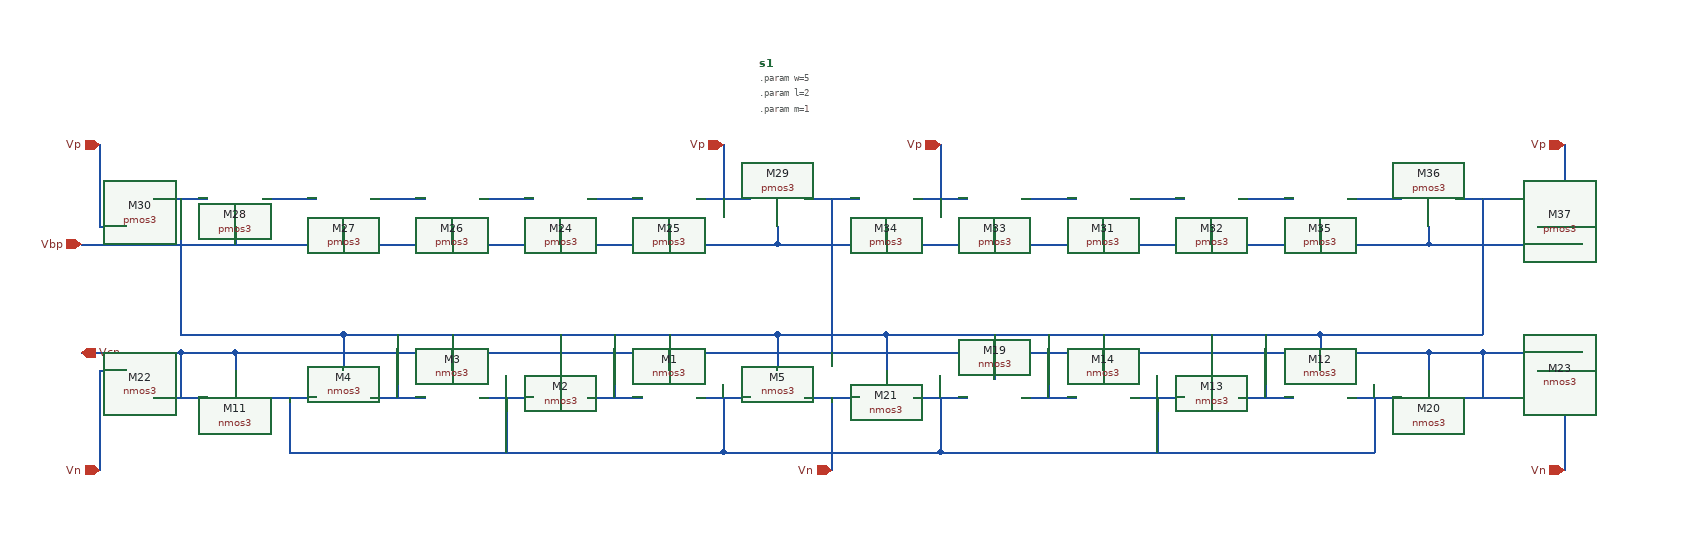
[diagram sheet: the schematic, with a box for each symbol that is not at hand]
v {xschem version=2.9.9 file_version=1.2 }
G {}
K {}
V {}
S {}
E {}
N -1100 -150 -1040 -150 { lab=#net1}
N -1220 -150 -1160 -150 { lab=#net2}
N -1340 -150 -1280 -150 { lab=#net1}
N -1460 -150 -1400 -150 { lab=#net2}
N -980 -150 -920 -150 { lab=#net2}
N -830 -150 -830 -70 { lab=Vn}
N -1370 -220 -890 -220 { lab=#net1}
N -1430 -150 -1430 -90 { lab=#net2}
N -1430 -90 -950 -90 { lab=#net2}
N -950 -150 -950 -90 { lab=#net2}
N -1190 -150 -1190 -90 { lab=#net2}
N -1580 -150 -1520 -150 { lab=Vcn}
N -1550 -200 -1550 -150 { lab=Vcn}
N -1550 -200 -1490 -200 { lab=Vcn}
N -1490 -200 -1490 -180 { lab=Vcn}
N -1370 -220 -1370 -180 { lab=#net1}
N -1250 -220 -1250 -180 { lab=#net1}
N -1130 -220 -1130 -180 { lab=#net1}
N -1010 -220 -1010 -180 { lab=#net1}
N -890 -220 -890 -180 { lab=#net1}
N -380 -150 -320 -150 { lab=#net1}
N -500 -150 -440 -150 { lab=#net2}
N -620 -150 -560 -150 { lab=#net1}
N -740 -150 -680 -150 { lab=#net2}
N -260 -150 -200 -150 { lab=#net2}
N -860 -150 -800 -150 { lab=Vn}
N -770 -220 -770 -180 { lab=#net1}
N -770 -220 -290 -220 { lab=#net1}
N -290 -220 -290 -180 { lab=#net1}
N -710 -150 -710 -90 { lab=#net2}
N -470 -150 -470 -90 { lab=#net2}
N -230 -150 -230 -90 { lab=#net2}
N -710 -90 -230 -90 { lab=#net2}
N -170 -200 -170 -180 { lab=Vcn}
N -140 -150 -80 -150 { lab=Vcn}
N -110 -200 -110 -150 { lab=Vcn}
N -170 -200 -110 -200 { lab=Vcn}
N -650 -220 -650 -170 { lab=#net1}
N -530 -220 -530 -180 { lab=#net1}
N -410 -220 -410 -180 { lab=#net1}
N -1490 -200 -170 -200 { lab=Vcn}
N -1640 -180 -1610 -180 { lab=Vn}
N -1640 -180 -1640 -70 { lab=Vn}
N -1660 -200 -1550 -200 { lab=Vcn}
N -50 -180 -20 -180 { lab=Vn}
N -20 -180 -20 -70 { lab=Vn}
N -110 -200 0 -200 { lab=Vcn}
N -1100 -370 -1040 -370 { lab=#net3}
N -1220 -370 -1160 -370 { lab=#net4}
N -1340 -370 -1280 -370 { lab=#net5}
N -1460 -370 -1400 -370 { lab=Vp}
N -1490 -340 -1490 -320 { lab=Vbp}
N -1370 -340 -1370 -320 { lab=Vbp}
N -1250 -340 -1250 -320 { lab=Vbp}
N -1130 -340 -1130 -320 { lab=Vbp}
N -1010 -340 -1010 -320 { lab=Vbp}
N -980 -370 -920 -370 { lab=#net6}
N -890 -340 -890 -320 { lab=Vbp}
N -950 -430 -950 -370 { lab=Vp}
N -1580 -370 -1520 -370 { lab=Vcn}
N -1640 -340 -1610 -340 { lab=Vp}
N -1640 -370 -1640 -340 { lab=Vp}
N -1640 -430 -1640 -370 { lab=Vp}
N -1660 -320 -890 -320 { lab=Vbp}
N -860 -370 -800 -370 { lab=#net1}
N -890 -220 -770 -220 { lab=#net1}
N -500 -370 -440 -370 { lab=#net7}
N -620 -370 -560 -370 { lab=#net8}
N -740 -370 -680 -370 { lab=#net9}
N -770 -340 -770 -320 { lab=Vbp}
N -650 -340 -650 -320 { lab=Vbp}
N -530 -340 -530 -320 { lab=Vbp}
N -410 -340 -410 -320 { lab=Vbp}
N -380 -370 -320 -370 { lab=#net10}
N -290 -340 -290 -320 { lab=Vbp}
N -260 -370 -200 -370 { lab=Vp}
N -170 -340 -170 -320 { lab=Vbp}
N -140 -370 -80 -370 { lab=Vcn}
N -890 -320 -170 -320 { lab=Vbp}
N -170 -320 0 -320 { lab=Vbp}
N -50 -340 -20 -340 { lab=Vp}
N -20 -430 -20 -340 { lab=Vp}
N -950 -90 -710 -90 { lab=#net2}
N -350 -220 -350 -150 { lab=#net1}
N -590 -220 -590 -150 { lab=#net1}
N -1070 -220 -1070 -150 { lab=#net1}
N -1310 -220 -1310 -150 { lab=#net1}
N -830 -370 -830 -200 {}
N -1550 -370 -1550 -220 {}
N -710 -430 -710 -370 { lab=Vp}
N -110 -370 -110 -220 {}
N -290 -220 -110 -220 {}
N -1550 -220 -1370 -220 {}
C {devices/code_shown.sym} -910 -520 0 0 {name=s1 only_toplevel=false value="
.param w=5
.param l=2
.param m=1
"}
C {madvlsi/nmos3.sym} -1010 -150 1 0 {name=M1
L=l
W=w
body=GND
nf=1
mult=m
ad="'int((nf+1)/2) * W/nf * 0.29'" 
pd="'2*int((nf+1)/2) * (W/nf + 0.29)'"
as="'int((nf+2)/2) * W/nf * 0.29'" 
ps="'2*int((nf+2)/2) * (W/nf + 0.29)'"
nrd="'0.29 / W'" nrs="'0.29 / W'"
sa=0 sb=0 sd=0
model=nfet_01v8
spiceprefix=X
}
C {madvlsi/nmos3.sym} -1130 -150 1 0 {name=M2
L=l
W=w
body=GND
nf=1
mult=m
ad="'int((nf+1)/2) * W/nf * 0.29'" 
pd="'2*int((nf+1)/2) * (W/nf + 0.29)'"
as="'int((nf+2)/2) * W/nf * 0.29'" 
ps="'2*int((nf+2)/2) * (W/nf + 0.29)'"
nrd="'0.29 / W'" nrs="'0.29 / W'"
sa=0 sb=0 sd=0
model=nfet_01v8
spiceprefix=X
}
C {madvlsi/nmos3.sym} -1250 -150 1 0 {name=M3
L=l
W=w
body=GND
nf=1
mult=m
ad="'int((nf+1)/2) * W/nf * 0.29'" 
pd="'2*int((nf+1)/2) * (W/nf + 0.29)'"
as="'int((nf+2)/2) * W/nf * 0.29'" 
ps="'2*int((nf+2)/2) * (W/nf + 0.29)'"
nrd="'0.29 / W'" nrs="'0.29 / W'"
sa=0 sb=0 sd=0
model=nfet_01v8
spiceprefix=X
}
C {madvlsi/nmos3.sym} -1370 -150 1 0 {name=M4
L=l
W=w
body=GND
nf=1
mult=m
ad="'int((nf+1)/2) * W/nf * 0.29'" 
pd="'2*int((nf+1)/2) * (W/nf + 0.29)'"
as="'int((nf+2)/2) * W/nf * 0.29'" 
ps="'2*int((nf+2)/2) * (W/nf + 0.29)'"
nrd="'0.29 / W'" nrs="'0.29 / W'"
sa=0 sb=0 sd=0
model=nfet_01v8
spiceprefix=X
}
C {madvlsi/nmos3.sym} -890 -150 1 0 {name=M5
L=l
W=w
body=GND
nf=1
mult=m
ad="'int((nf+1)/2) * W/nf * 0.29'" 
pd="'2*int((nf+1)/2) * (W/nf + 0.29)'"
as="'int((nf+2)/2) * W/nf * 0.29'" 
ps="'2*int((nf+2)/2) * (W/nf + 0.29)'"
nrd="'0.29 / W'" nrs="'0.29 / W'"
sa=0 sb=0 sd=0
model=nfet_01v8
spiceprefix=X
}
C {madvlsi/nmos3.sym} -1490 -150 1 0 {name=M11
L=l
W=w
body=GND
nf=1
mult=m
ad="'int((nf+1)/2) * W/nf * 0.29'" 
pd="'2*int((nf+1)/2) * (W/nf + 0.29)'"
as="'int((nf+2)/2) * W/nf * 0.29'" 
ps="'2*int((nf+2)/2) * (W/nf + 0.29)'"
nrd="'0.29 / W'" nrs="'0.29 / W'"
sa=0 sb=0 sd=0
model=nfet_01v8
spiceprefix=X
}
C {devices/iopin.sym} -830 -70 1 0 {name=p2 lab=Vn}
C {madvlsi/nmos3.sym} -290 -150 1 0 {name=M12
L=l
W=w
body=GND
nf=1
mult=m
ad="'int((nf+1)/2) * W/nf * 0.29'" 
pd="'2*int((nf+1)/2) * (W/nf + 0.29)'"
as="'int((nf+2)/2) * W/nf * 0.29'" 
ps="'2*int((nf+2)/2) * (W/nf + 0.29)'"
nrd="'0.29 / W'" nrs="'0.29 / W'"
sa=0 sb=0 sd=0
model=nfet_01v8
spiceprefix=X
}
C {madvlsi/nmos3.sym} -410 -150 1 0 {name=M13
L=l
W=w
body=GND
nf=1
mult=m
ad="'int((nf+1)/2) * W/nf * 0.29'" 
pd="'2*int((nf+1)/2) * (W/nf + 0.29)'"
as="'int((nf+2)/2) * W/nf * 0.29'" 
ps="'2*int((nf+2)/2) * (W/nf + 0.29)'"
nrd="'0.29 / W'" nrs="'0.29 / W'"
sa=0 sb=0 sd=0
model=nfet_01v8
spiceprefix=X
}
C {madvlsi/nmos3.sym} -530 -150 1 0 {name=M14
L=l
W=w
body=GND
nf=1
mult=m
ad="'int((nf+1)/2) * W/nf * 0.29'" 
pd="'2*int((nf+1)/2) * (W/nf + 0.29)'"
as="'int((nf+2)/2) * W/nf * 0.29'" 
ps="'2*int((nf+2)/2) * (W/nf + 0.29)'"
nrd="'0.29 / W'" nrs="'0.29 / W'"
sa=0 sb=0 sd=0
model=nfet_01v8
spiceprefix=X
}
C {madvlsi/nmos3.sym} -650 -150 1 0 {name=M19
L=l
W=w
body=GND
nf=1
mult=m
ad="'int((nf+1)/2) * W/nf * 0.29'" 
pd="'2*int((nf+1)/2) * (W/nf + 0.29)'"
as="'int((nf+2)/2) * W/nf * 0.29'" 
ps="'2*int((nf+2)/2) * (W/nf + 0.29)'"
nrd="'0.29 / W'" nrs="'0.29 / W'"
sa=0 sb=0 sd=0
model=nfet_01v8
spiceprefix=X
}
C {madvlsi/nmos3.sym} -170 -150 1 0 {name=M20
L=l
W=w
body=GND
nf=1
mult=m
ad="'int((nf+1)/2) * W/nf * 0.29'" 
pd="'2*int((nf+1)/2) * (W/nf + 0.29)'"
as="'int((nf+2)/2) * W/nf * 0.29'" 
ps="'2*int((nf+2)/2) * (W/nf + 0.29)'"
nrd="'0.29 / W'" nrs="'0.29 / W'"
sa=0 sb=0 sd=0
model=nfet_01v8
spiceprefix=X
}
C {madvlsi/nmos3.sym} -770 -150 1 0 {name=M21
L=l
W=w
body=GND
nf=1
mult=m
ad="'int((nf+1)/2) * W/nf * 0.29'" 
pd="'2*int((nf+1)/2) * (W/nf + 0.29)'"
as="'int((nf+2)/2) * W/nf * 0.29'" 
ps="'2*int((nf+2)/2) * (W/nf + 0.29)'"
nrd="'0.29 / W'" nrs="'0.29 / W'"
sa=0 sb=0 sd=0
model=nfet_01v8
spiceprefix=X
}
C {devices/opin.sym} -1660 -200 2 0 {name=p5 lab=Vcn}
C {madvlsi/nmos3.sym} -1610 -150 1 0 {name=M22
L=l
W=w
body=GND
nf=1
mult=m
ad="'int((nf+1)/2) * W/nf * 0.29'" 
pd="'2*int((nf+1)/2) * (W/nf + 0.29)'"
as="'int((nf+2)/2) * W/nf * 0.29'" 
ps="'2*int((nf+2)/2) * (W/nf + 0.29)'"
nrd="'0.29 / W'" nrs="'0.29 / W'"
sa=0 sb=0 sd=0
model=nfet_01v8
spiceprefix=X
}
C {devices/iopin.sym} -1640 -70 1 0 {name=p7 lab=Vn}
C {madvlsi/nmos3.sym} -50 -150 1 0 {name=M23
L=l
W=w
body=GND
nf=1
mult=m
ad="'int((nf+1)/2) * W/nf * 0.29'" 
pd="'2*int((nf+1)/2) * (W/nf + 0.29)'"
as="'int((nf+2)/2) * W/nf * 0.29'" 
ps="'2*int((nf+2)/2) * (W/nf + 0.29)'"
nrd="'0.29 / W'" nrs="'0.29 / W'"
sa=0 sb=0 sd=0
model=nfet_01v8
spiceprefix=X
}
C {devices/iopin.sym} -20 -70 1 0 {name=p8 lab=Vn}
C {madvlsi/pmos3.sym} -1130 -370 3 0 {name=M24
L=l
W=w
body=VDD
nf=1
mult=m
ad="'int((nf+1)/2) * W/nf * 0.29'" 
pd="'2*int((nf+1)/2) * (W/nf + 0.29)'"
as="'int((nf+2)/2) * W/nf * 0.29'" 
ps="'2*int((nf+2)/2) * (W/nf + 0.29)'"
nrd="'0.29 / W'" nrs="'0.29 / W'"
sa=0 sb=0 sd=0
model=pfet_01v8
spiceprefix=X
}
C {madvlsi/pmos3.sym} -1010 -370 3 0 {name=M25
L=l
W=w
body=VDD
nf=1
mult=m
ad="'int((nf+1)/2) * W/nf * 0.29'" 
pd="'2*int((nf+1)/2) * (W/nf + 0.29)'"
as="'int((nf+2)/2) * W/nf * 0.29'" 
ps="'2*int((nf+2)/2) * (W/nf + 0.29)'"
nrd="'0.29 / W'" nrs="'0.29 / W'"
sa=0 sb=0 sd=0
model=pfet_01v8
spiceprefix=X
}
C {madvlsi/pmos3.sym} -1250 -370 3 0 {name=M26
L=l
W=w
body=VDD
nf=1
mult=m
ad="'int((nf+1)/2) * W/nf * 0.29'" 
pd="'2*int((nf+1)/2) * (W/nf + 0.29)'"
as="'int((nf+2)/2) * W/nf * 0.29'" 
ps="'2*int((nf+2)/2) * (W/nf + 0.29)'"
nrd="'0.29 / W'" nrs="'0.29 / W'"
sa=0 sb=0 sd=0
model=pfet_01v8
spiceprefix=X
}
C {madvlsi/pmos3.sym} -1370 -370 3 0 {name=M27
L=l
W=w
body=VDD
nf=1
mult=m
ad="'int((nf+1)/2) * W/nf * 0.29'" 
pd="'2*int((nf+1)/2) * (W/nf + 0.29)'"
as="'int((nf+2)/2) * W/nf * 0.29'" 
ps="'2*int((nf+2)/2) * (W/nf + 0.29)'"
nrd="'0.29 / W'" nrs="'0.29 / W'"
sa=0 sb=0 sd=0
model=pfet_01v8
spiceprefix=X
}
C {madvlsi/pmos3.sym} -1490 -370 3 0 {name=M28
L=l
W=w
body=VDD
nf=1
mult=m
ad="'int((nf+1)/2) * W/nf * 0.29'" 
pd="'2*int((nf+1)/2) * (W/nf + 0.29)'"
as="'int((nf+2)/2) * W/nf * 0.29'" 
ps="'2*int((nf+2)/2) * (W/nf + 0.29)'"
nrd="'0.29 / W'" nrs="'0.29 / W'"
sa=0 sb=0 sd=0
model=pfet_01v8
spiceprefix=X
}
C {madvlsi/pmos3.sym} -890 -370 3 0 {name=M29
L=l
W=w
body=VDD
nf=1
mult=m
ad="'int((nf+1)/2) * W/nf * 0.29'" 
pd="'2*int((nf+1)/2) * (W/nf + 0.29)'"
as="'int((nf+2)/2) * W/nf * 0.29'" 
ps="'2*int((nf+2)/2) * (W/nf + 0.29)'"
nrd="'0.29 / W'" nrs="'0.29 / W'"
sa=0 sb=0 sd=0
model=pfet_01v8
spiceprefix=X
}
C {devices/iopin.sym} -950 -430 3 0 {name=p9 lab=Vp}
C {madvlsi/pmos3.sym} -1610 -370 3 0 {name=M30
L=l
W=w
body=VDD
nf=1
mult=m
ad="'int((nf+1)/2) * W/nf * 0.29'" 
pd="'2*int((nf+1)/2) * (W/nf + 0.29)'"
as="'int((nf+2)/2) * W/nf * 0.29'" 
ps="'2*int((nf+2)/2) * (W/nf + 0.29)'"
nrd="'0.29 / W'" nrs="'0.29 / W'"
sa=0 sb=0 sd=0
model=pfet_01v8
spiceprefix=X
}
C {devices/iopin.sym} -1640 -430 3 0 {name=p10 lab=Vp}
C {devices/ipin.sym} -1660 -320 0 0 {name=p11 lab=Vbp}
C {madvlsi/pmos3.sym} -530 -370 3 0 {name=M31
L=l
W=w
body=VDD
nf=1
mult=m
ad="'int((nf+1)/2) * W/nf * 0.29'" 
pd="'2*int((nf+1)/2) * (W/nf + 0.29)'"
as="'int((nf+2)/2) * W/nf * 0.29'" 
ps="'2*int((nf+2)/2) * (W/nf + 0.29)'"
nrd="'0.29 / W'" nrs="'0.29 / W'"
sa=0 sb=0 sd=0
model=pfet_01v8
spiceprefix=X
}
C {madvlsi/pmos3.sym} -410 -370 3 0 {name=M32
L=l
W=w
body=VDD
nf=1
mult=m
ad="'int((nf+1)/2) * W/nf * 0.29'" 
pd="'2*int((nf+1)/2) * (W/nf + 0.29)'"
as="'int((nf+2)/2) * W/nf * 0.29'" 
ps="'2*int((nf+2)/2) * (W/nf + 0.29)'"
nrd="'0.29 / W'" nrs="'0.29 / W'"
sa=0 sb=0 sd=0
model=pfet_01v8
spiceprefix=X
}
C {madvlsi/pmos3.sym} -650 -370 3 0 {name=M33
L=l
W=w
body=VDD
nf=1
mult=m
ad="'int((nf+1)/2) * W/nf * 0.29'" 
pd="'2*int((nf+1)/2) * (W/nf + 0.29)'"
as="'int((nf+2)/2) * W/nf * 0.29'" 
ps="'2*int((nf+2)/2) * (W/nf + 0.29)'"
nrd="'0.29 / W'" nrs="'0.29 / W'"
sa=0 sb=0 sd=0
model=pfet_01v8
spiceprefix=X
}
C {madvlsi/pmos3.sym} -770 -370 3 0 {name=M34
L=l
W=w
body=VDD
nf=1
mult=m
ad="'int((nf+1)/2) * W/nf * 0.29'" 
pd="'2*int((nf+1)/2) * (W/nf + 0.29)'"
as="'int((nf+2)/2) * W/nf * 0.29'" 
ps="'2*int((nf+2)/2) * (W/nf + 0.29)'"
nrd="'0.29 / W'" nrs="'0.29 / W'"
sa=0 sb=0 sd=0
model=pfet_01v8
spiceprefix=X
}
C {madvlsi/pmos3.sym} -290 -370 3 0 {name=M35
L=l
W=w
body=VDD
nf=1
mult=m
ad="'int((nf+1)/2) * W/nf * 0.29'" 
pd="'2*int((nf+1)/2) * (W/nf + 0.29)'"
as="'int((nf+2)/2) * W/nf * 0.29'" 
ps="'2*int((nf+2)/2) * (W/nf + 0.29)'"
nrd="'0.29 / W'" nrs="'0.29 / W'"
sa=0 sb=0 sd=0
model=pfet_01v8
spiceprefix=X
}
C {madvlsi/pmos3.sym} -170 -370 3 0 {name=M36
L=l
W=w
body=VDD
nf=1
mult=m
ad="'int((nf+1)/2) * W/nf * 0.29'" 
pd="'2*int((nf+1)/2) * (W/nf + 0.29)'"
as="'int((nf+2)/2) * W/nf * 0.29'" 
ps="'2*int((nf+2)/2) * (W/nf + 0.29)'"
nrd="'0.29 / W'" nrs="'0.29 / W'"
sa=0 sb=0 sd=0
model=pfet_01v8
spiceprefix=X
}
C {madvlsi/pmos3.sym} -50 -370 3 0 {name=M37
L=l
W=w
body=VDD
nf=1
mult=m
ad="'int((nf+1)/2) * W/nf * 0.29'" 
pd="'2*int((nf+1)/2) * (W/nf + 0.29)'"
as="'int((nf+2)/2) * W/nf * 0.29'" 
ps="'2*int((nf+2)/2) * (W/nf + 0.29)'"
nrd="'0.29 / W'" nrs="'0.29 / W'"
sa=0 sb=0 sd=0
model=pfet_01v8
spiceprefix=X
}
C {devices/iopin.sym} -20 -430 3 0 {name=p13 lab=Vp}
C {devices/iopin.sym} -710 -430 3 0 {name=p1 lab=Vp}
